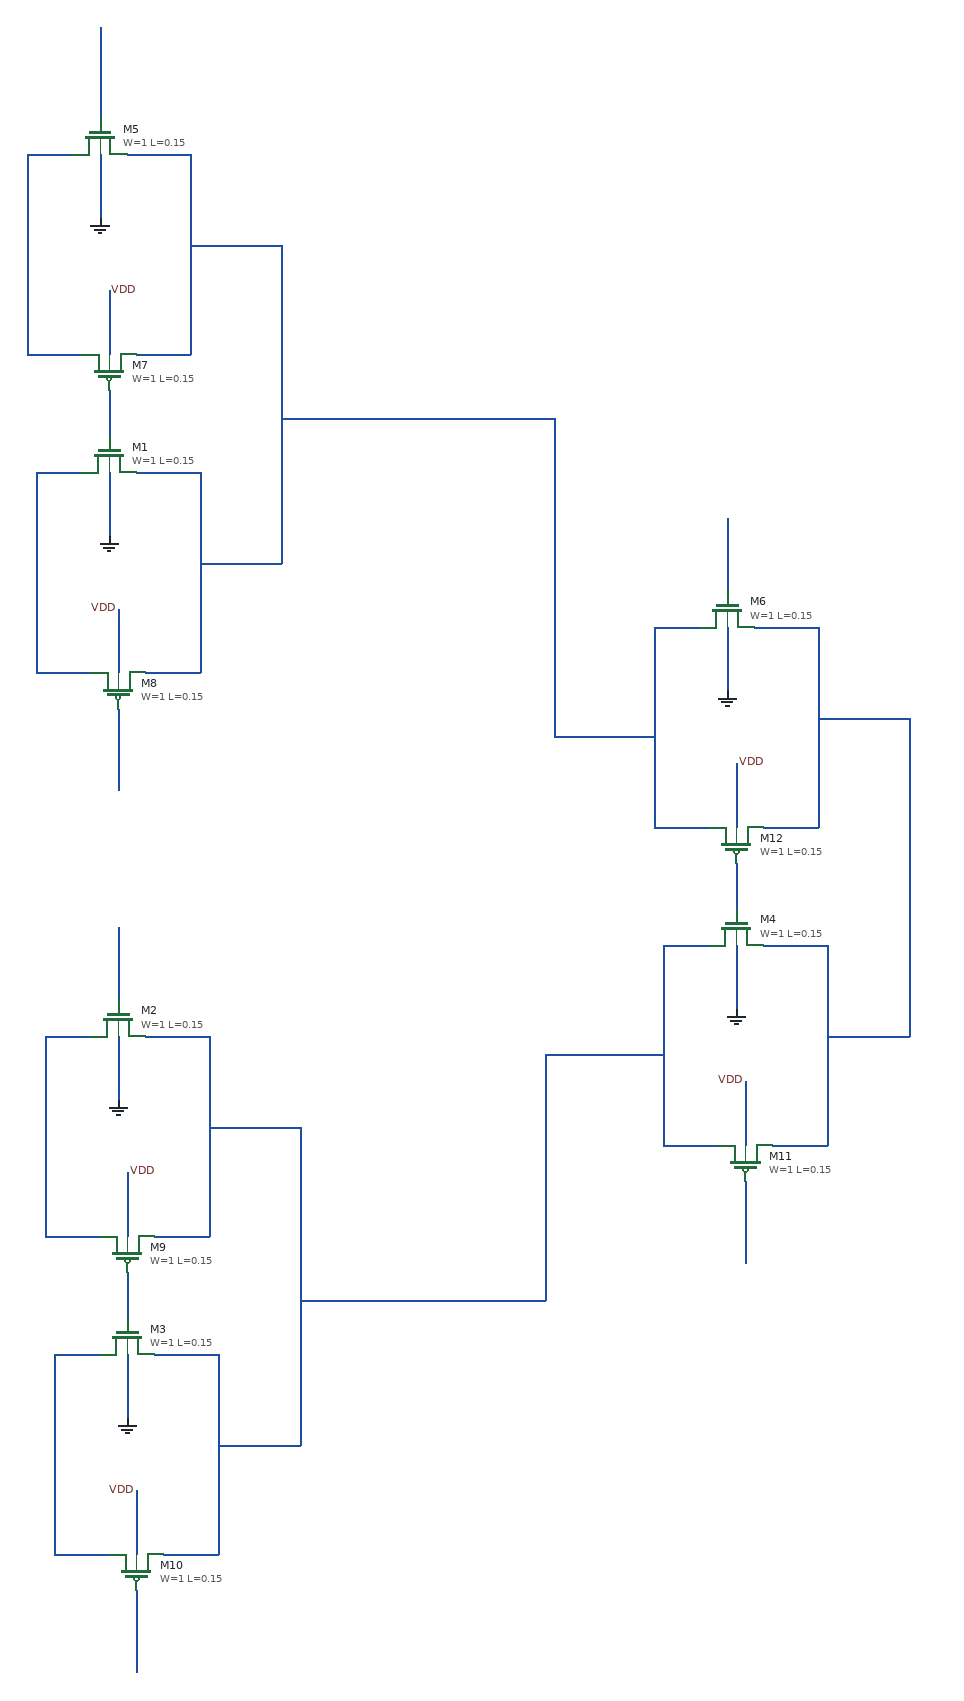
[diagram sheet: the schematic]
v {xschem version=3.4.5 file_version=1.2
}
G {}
K {}
V {}
S {}
E {}
N 500 -1850 570 -1850 {
lab=#net1}
N 570 -1850 570 -1630 {
lab=#net1}
N 510 -1630 570 -1630 {
lab=#net1}
N 390 -1850 440 -1850 {
lab=#net2}
N 390 -1850 390 -1630 {
lab=#net2}
N 390 -1630 450 -1630 {
lab=#net2}
N 470 -1850 470 -1780 {
lab=GND}
N 480 -1700 480 -1630 {
lab=VDD}
N 510 -1500 580 -1500 {
lab=#net1}
N 580 -1500 580 -1280 {
lab=#net1}
N 520 -1280 580 -1280 {
lab=#net1}
N 400 -1500 450 -1500 {
lab=#net3}
N 400 -1500 400 -1280 {
lab=#net3}
N 400 -1280 460 -1280 {
lab=#net3}
N 480 -1500 480 -1430 {
lab=GND}
N 490 -1350 490 -1280 {
lab=VDD}
N 480 -1590 480 -1540 {
lab=#net4}
N 570 -1750 670 -1750 {
lab=#net1}
N 670 -1750 670 -1400 {
lab=#net1}
N 580 -1400 670 -1400 {
lab=#net1}
N 670 -1560 770 -1560 {
lab=#net1}
N 490 -1240 490 -1150 {
lab=#net5}
N 520 -880 590 -880 {
lab=#net6}
N 590 -880 590 -660 {
lab=#net6}
N 530 -660 590 -660 {
lab=#net6}
N 410 -880 460 -880 {
lab=#net7}
N 410 -880 410 -660 {
lab=#net7}
N 410 -660 470 -660 {
lab=#net7}
N 490 -880 490 -810 {
lab=GND}
N 500 -730 500 -660 {
lab=VDD}
N 530 -530 600 -530 {
lab=#net6}
N 600 -530 600 -310 {
lab=#net6}
N 540 -310 600 -310 {
lab=#net6}
N 420 -530 470 -530 {
lab=#net8}
N 420 -530 420 -310 {
lab=#net8}
N 420 -310 480 -310 {
lab=#net8}
N 500 -530 500 -460 {
lab=GND}
N 510 -380 510 -310 {
lab=VDD}
N 500 -620 500 -570 {
lab=#net9}
N 590 -780 690 -780 {
lab=#net6}
N 690 -780 690 -430 {
lab=#net6}
N 600 -430 690 -430 {
lab=#net6}
N 690 -590 790 -590 {
lab=#net6}
N 490 -1000 490 -920 {
lab=#net10}
N 510 -270 510 -180 {
lab=#net11}
N 1190 -1330 1260 -1330 {
lab=out}
N 1260 -1330 1260 -1110 {
lab=out}
N 1200 -1110 1260 -1110 {
lab=out}
N 1080 -1330 1130 -1330 {
lab=#net1}
N 1080 -1330 1080 -1110 {
lab=#net1}
N 1080 -1110 1140 -1110 {
lab=#net1}
N 1160 -1330 1160 -1260 {
lab=GND}
N 1170 -1180 1170 -1110 {
lab=VDD}
N 1200 -980 1270 -980 {
lab=out}
N 1270 -980 1270 -760 {
lab=out}
N 1210 -760 1270 -760 {
lab=out}
N 1090 -980 1140 -980 {
lab=#net6}
N 1090 -980 1090 -760 {
lab=#net6}
N 1090 -760 1150 -760 {
lab=#net6}
N 1170 -980 1170 -910 {
lab=GND}
N 1180 -830 1180 -760 {
lab=VDD}
N 1170 -1070 1170 -1020 {
lab=#net12}
N 1260 -1230 1360 -1230 {
lab=out}
N 1360 -1230 1360 -880 {
lab=out}
N 1270 -880 1360 -880 {
lab=out}
N 980 -1210 1080 -1210 {
lab=#net1}
N 960 -860 1090 -860 {
lab=#net6}
N 1160 -1450 1160 -1370 {
lab=#net13}
N 1180 -720 1180 -630 {
lab=#net14}
N 770 -1560 970 -1560 {
lab=#net1}
N 970 -1560 970 -1220 {
lab=#net1}
N 970 -1220 970 -1210 {
lab=#net1}
N 790 -590 960 -590 {
lab=#net6}
N 960 -860 960 -590 {
lab=#net6}
N 970 -1210 980 -1210 {
lab=#net1}
N 470 -1990 470 -1890 {
lab=#net15}
C {devices/gnd.sym} 470 -1780 0 0 {name=l4 lab=GND}
C {devices/lab_pin.sym} 490 -1350 1 0 {name=p21 sig_type=std_logic lab=VDD}
C {devices/lab_pin.sym} 480 -1700 2 0 {name=p22 sig_type=std_logic lab=VDD}
C {devices/gnd.sym} 480 -1430 0 0 {name=l6 lab=GND}
C {devices/gnd.sym} 490 -810 0 0 {name=l9 lab=GND}
C {devices/lab_pin.sym} 510 -380 1 0 {name=p30 sig_type=std_logic lab=VDD}
C {devices/lab_pin.sym} 500 -730 2 0 {name=p31 sig_type=std_logic lab=VDD}
C {devices/gnd.sym} 500 -460 0 0 {name=l12 lab=GND}
C {devices/gnd.sym} 1160 -1260 0 0 {name=l13 lab=GND}
C {devices/lab_pin.sym} 1180 -830 1 0 {name=p39 sig_type=std_logic lab=VDD}
C {devices/lab_pin.sym} 1170 -1180 2 0 {name=p40 sig_type=std_logic lab=VDD}
C {devices/gnd.sym} 1170 -910 0 0 {name=l14 lab=GND}
C {sky130_fd_pr/nfet_01v8.sym} 470 -1870 1 0 {name=M5
L=0.15
W=1
nf=1 
mult=1
ad="'int((nf+1)/2) * W/nf * 0.29'" 
pd="'2*int((nf+1)/2) * (W/nf + 0.29)'"
as="'int((nf+2)/2) * W/nf * 0.29'" 
ps="'2*int((nf+2)/2) * (W/nf + 0.29)'"
nrd="'0.29 / W'" nrs="'0.29 / W'"
sa=0 sb=0 sd=0
model=nfet_01v8
spiceprefix=X
}
C {sky130_fd_pr/nfet_01v8.sym} 480 -1520 1 0 {name=M1
L=0.15
W=1
nf=1 
mult=1
ad="'int((nf+1)/2) * W/nf * 0.29'" 
pd="'2*int((nf+1)/2) * (W/nf + 0.29)'"
as="'int((nf+2)/2) * W/nf * 0.29'" 
ps="'2*int((nf+2)/2) * (W/nf + 0.29)'"
nrd="'0.29 / W'" nrs="'0.29 / W'"
sa=0 sb=0 sd=0
model=nfet_01v8
spiceprefix=X
}
C {sky130_fd_pr/nfet_01v8.sym} 490 -900 1 0 {name=M2
L=0.15
W=1
nf=1 
mult=1
ad="'int((nf+1)/2) * W/nf * 0.29'" 
pd="'2*int((nf+1)/2) * (W/nf + 0.29)'"
as="'int((nf+2)/2) * W/nf * 0.29'" 
ps="'2*int((nf+2)/2) * (W/nf + 0.29)'"
nrd="'0.29 / W'" nrs="'0.29 / W'"
sa=0 sb=0 sd=0
model=nfet_01v8
spiceprefix=X
}
C {sky130_fd_pr/nfet_01v8.sym} 500 -550 1 0 {name=M3
L=0.15
W=1
nf=1 
mult=1
ad="'int((nf+1)/2) * W/nf * 0.29'" 
pd="'2*int((nf+1)/2) * (W/nf + 0.29)'"
as="'int((nf+2)/2) * W/nf * 0.29'" 
ps="'2*int((nf+2)/2) * (W/nf + 0.29)'"
nrd="'0.29 / W'" nrs="'0.29 / W'"
sa=0 sb=0 sd=0
model=nfet_01v8
spiceprefix=X
}
C {sky130_fd_pr/nfet_01v8.sym} 1170 -1000 1 0 {name=M4
L=0.15
W=1
nf=1 
mult=1
ad="'int((nf+1)/2) * W/nf * 0.29'" 
pd="'2*int((nf+1)/2) * (W/nf + 0.29)'"
as="'int((nf+2)/2) * W/nf * 0.29'" 
ps="'2*int((nf+2)/2) * (W/nf + 0.29)'"
nrd="'0.29 / W'" nrs="'0.29 / W'"
sa=0 sb=0 sd=0
model=nfet_01v8
spiceprefix=X
}
C {sky130_fd_pr/nfet_01v8.sym} 1160 -1350 1 0 {name=M6
L=0.15
W=1
nf=1 
mult=1
ad="'int((nf+1)/2) * W/nf * 0.29'" 
pd="'2*int((nf+1)/2) * (W/nf + 0.29)'"
as="'int((nf+2)/2) * W/nf * 0.29'" 
ps="'2*int((nf+2)/2) * (W/nf + 0.29)'"
nrd="'0.29 / W'" nrs="'0.29 / W'"
sa=0 sb=0 sd=0
model=nfet_01v8
spiceprefix=X
}
C {sky130_fd_pr/pfet_01v8.sym} 480 -1610 3 0 {name=M7
L=0.15
W=1
nf=1
mult=1
ad="'int((nf+1)/2) * W/nf * 0.29'" 
pd="'2*int((nf+1)/2) * (W/nf + 0.29)'"
as="'int((nf+2)/2) * W/nf * 0.29'" 
ps="'2*int((nf+2)/2) * (W/nf + 0.29)'"
nrd="'0.29 / W'" nrs="'0.29 / W'"
sa=0 sb=0 sd=0
model=pfet_01v8
spiceprefix=X
}
C {sky130_fd_pr/pfet_01v8.sym} 490 -1260 3 0 {name=M8
L=0.15
W=1
nf=1
mult=1
ad="'int((nf+1)/2) * W/nf * 0.29'" 
pd="'2*int((nf+1)/2) * (W/nf + 0.29)'"
as="'int((nf+2)/2) * W/nf * 0.29'" 
ps="'2*int((nf+2)/2) * (W/nf + 0.29)'"
nrd="'0.29 / W'" nrs="'0.29 / W'"
sa=0 sb=0 sd=0
model=pfet_01v8
spiceprefix=X
}
C {sky130_fd_pr/pfet_01v8.sym} 500 -640 3 0 {name=M9
L=0.15
W=1
nf=1
mult=1
ad="'int((nf+1)/2) * W/nf * 0.29'" 
pd="'2*int((nf+1)/2) * (W/nf + 0.29)'"
as="'int((nf+2)/2) * W/nf * 0.29'" 
ps="'2*int((nf+2)/2) * (W/nf + 0.29)'"
nrd="'0.29 / W'" nrs="'0.29 / W'"
sa=0 sb=0 sd=0
model=pfet_01v8
spiceprefix=X
}
C {sky130_fd_pr/pfet_01v8.sym} 510 -290 3 0 {name=M10
L=0.15
W=1
nf=1
mult=1
ad="'int((nf+1)/2) * W/nf * 0.29'" 
pd="'2*int((nf+1)/2) * (W/nf + 0.29)'"
as="'int((nf+2)/2) * W/nf * 0.29'" 
ps="'2*int((nf+2)/2) * (W/nf + 0.29)'"
nrd="'0.29 / W'" nrs="'0.29 / W'"
sa=0 sb=0 sd=0
model=pfet_01v8
spiceprefix=X
}
C {sky130_fd_pr/pfet_01v8.sym} 1180 -740 3 0 {name=M11
L=0.15
W=1
nf=1
mult=1
ad="'int((nf+1)/2) * W/nf * 0.29'" 
pd="'2*int((nf+1)/2) * (W/nf + 0.29)'"
as="'int((nf+2)/2) * W/nf * 0.29'" 
ps="'2*int((nf+2)/2) * (W/nf + 0.29)'"
nrd="'0.29 / W'" nrs="'0.29 / W'"
sa=0 sb=0 sd=0
model=pfet_01v8
spiceprefix=X
}
C {sky130_fd_pr/pfet_01v8.sym} 1170 -1090 3 0 {name=M12
L=0.15
W=1
nf=1
mult=1
ad="'int((nf+1)/2) * W/nf * 0.29'" 
pd="'2*int((nf+1)/2) * (W/nf + 0.29)'"
as="'int((nf+2)/2) * W/nf * 0.29'" 
ps="'2*int((nf+2)/2) * (W/nf + 0.29)'"
nrd="'0.29 / W'" nrs="'0.29 / W'"
sa=0 sb=0 sd=0
model=pfet_01v8
spiceprefix=X
}
